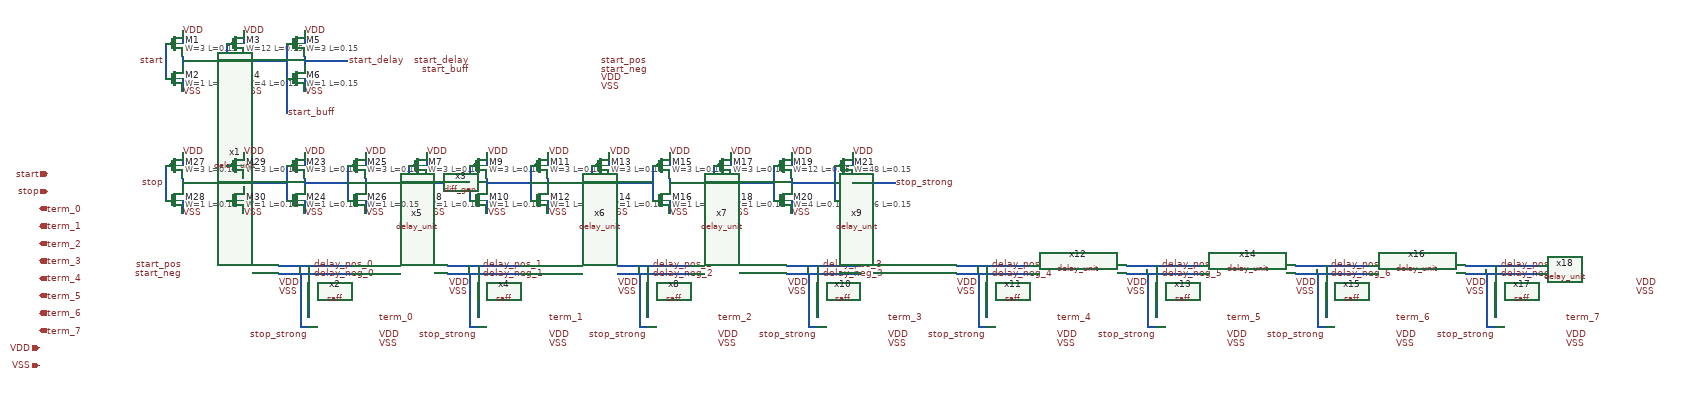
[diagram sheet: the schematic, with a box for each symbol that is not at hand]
v {xschem version=3.4.5 file_version=1.2
}
G {}
K {}
V {}
S {}
E {}
N 600 -270 770 -270 {
lab=delay_pos_0}
N 600 -250 770 -250 {
lab=delay_neg_0}
N 990 -270 1160 -270 {
lab=delay_pos_1}
N 990 -250 1160 -250 {
lab=delay_neg_1}
N 1380 -270 1550 -270 {
lab=delay_pos_2}
N 1380 -250 1550 -250 {
lab=delay_neg_2}
N 380 -750 380 -730 {
lab=#net1}
N 340 -780 340 -700 {
lab=start}
N 380 -810 380 -780 {
lab=VDD}
N 380 -700 380 -670 {
lab=VSS}
N 520 -750 520 -730 {
lab=start_buff}
N 480 -780 480 -700 {
lab=#net1}
N 520 -810 520 -780 {
lab=VDD}
N 520 -700 520 -670 {
lab=VSS}
N 660 -750 660 -730 {
lab=start_delay}
N 620 -780 620 -700 {
lab=start_buff}
N 660 -810 660 -780 {
lab=VDD}
N 660 -700 660 -670 {
lab=VSS}
N 380 -740 480 -740 {
lab=#net1}
N 520 -740 620 -740 {
lab=start_buff}
N 660 -740 760 -740 {
lab=start_delay}
N 620 -700 620 -620 {
lab=start_buff}
N 940 -470 940 -450 {
lab=#net2}
N 900 -500 900 -420 {
lab=#net3}
N 940 -530 940 -500 {
lab=VDD}
N 940 -420 940 -390 {
lab=VSS}
N 1080 -470 1080 -450 {
lab=#net4}
N 1040 -500 1040 -420 {
lab=#net2}
N 1080 -530 1080 -500 {
lab=VDD}
N 1080 -420 1080 -390 {
lab=VSS}
N 940 -460 1040 -460 {
lab=#net2}
N 1220 -470 1220 -450 {
lab=#net5}
N 1180 -500 1180 -420 {
lab=#net4}
N 1220 -530 1220 -500 {
lab=VDD}
N 1220 -420 1220 -390 {
lab=VSS}
N 1080 -460 1180 -460 {
lab=#net4}
N 1360 -470 1360 -450 {
lab=#net6}
N 1320 -500 1320 -420 {
lab=#net5}
N 1360 -530 1360 -500 {
lab=VDD}
N 1360 -420 1360 -390 {
lab=VSS}
N 1220 -460 1320 -460 {
lab=#net5}
N 1500 -470 1500 -450 {
lab=#net7}
N 1460 -500 1460 -420 {
lab=#net6}
N 1500 -530 1500 -500 {
lab=VDD}
N 1500 -420 1500 -390 {
lab=VSS}
N 1360 -460 1460 -460 {
lab=#net6}
N 1640 -470 1640 -450 {
lab=#net8}
N 1600 -500 1600 -420 {
lab=#net7}
N 1640 -530 1640 -500 {
lab=VDD}
N 1640 -420 1640 -390 {
lab=VSS}
N 1500 -460 1600 -460 {
lab=#net7}
N 1780 -470 1780 -450 {
lab=#net9}
N 1740 -500 1740 -420 {
lab=#net8}
N 1780 -530 1780 -500 {
lab=VDD}
N 1780 -420 1780 -390 {
lab=VSS}
N 1920 -470 1920 -450 {
lab=stop_strong}
N 1880 -500 1880 -420 {
lab=#net9}
N 1920 -530 1920 -500 {
lab=VDD}
N 1920 -420 1920 -390 {
lab=VSS}
N 1780 -460 1880 -460 {
lab=#net9}
N 1640 -460 1740 -460 {
lab=#net8}
N 1920 -460 2020 -460 {
lab=stop_strong}
N 670 -270 670 -150 {
lab=delay_pos_0}
N 650 -250 650 -130 {
lab=delay_neg_0}
N 650 -130 670 -130 {
lab=delay_neg_0}
N 1060 -270 1060 -150 {
lab=delay_pos_1}
N 1040 -250 1040 -130 {
lab=delay_neg_1}
N 1040 -130 1060 -130 {
lab=delay_neg_1}
N 1450 -270 1450 -150 {
lab=delay_pos_2}
N 1430 -250 1430 -130 {
lab=delay_neg_2}
N 1430 -130 1450 -130 {
lab=delay_neg_2}
N 1820 -250 1820 -130 {
lab=delay_neg_3}
N 1820 -130 1840 -130 {
lab=delay_neg_3}
N 2230 -270 2230 -150 {
lab=delay_pos_4}
N 2210 -250 2210 -130 {
lab=delay_neg_4}
N 2210 -130 2230 -130 {
lab=delay_neg_4}
N 1770 -250 1940 -250 {
lab=delay_neg_3}
N 1770 -270 1940 -270 {
lab=delay_pos_3}
N 1840 -270 1840 -150 {
lab=delay_pos_3}
N 2160 -250 2330 -250 {
lab=delay_neg_4}
N 2160 -270 2330 -270 {
lab=delay_pos_4}
N 660 -470 660 -450 {
lab=#net10}
N 620 -500 620 -420 {
lab=#net11}
N 660 -530 660 -500 {
lab=VDD}
N 660 -420 660 -390 {
lab=VSS}
N 800 -470 800 -450 {
lab=#net3}
N 760 -500 760 -420 {
lab=#net10}
N 800 -530 800 -500 {
lab=VDD}
N 800 -420 800 -390 {
lab=VSS}
N 660 -460 760 -460 {
lab=#net10}
N 800 -460 900 -460 {
lab=#net3}
N 380 -470 380 -450 {
lab=#net12}
N 340 -500 340 -420 {
lab=stop}
N 380 -530 380 -500 {
lab=VDD}
N 380 -420 380 -390 {
lab=VSS}
N 520 -470 520 -450 {
lab=#net11}
N 480 -500 480 -420 {
lab=#net12}
N 520 -530 520 -500 {
lab=VDD}
N 520 -420 520 -390 {
lab=VSS}
N 380 -460 480 -460 {
lab=#net12}
N 520 -460 620 -460 {
lab=#net11}
N 2620 -270 2620 -150 {
lab=delay_pos_4}
N 2600 -250 2600 -130 {
lab=delay_neg_4}
N 2600 -130 2620 -130 {
lab=delay_neg_4}
N 2550 -250 2720 -250 {
lab=delay_neg_4}
N 2550 -270 2720 -270 {
lab=delay_pos_4}
N 3010 -270 3010 -150 {
lab=delay_pos_4}
N 2990 -250 2990 -130 {
lab=delay_neg_4}
N 2990 -130 3010 -130 {
lab=delay_neg_4}
N 2940 -250 3110 -250 {
lab=delay_neg_4}
N 2940 -270 3110 -270 {
lab=delay_pos_4}
N 3400 -270 3400 -150 {
lab=delay_pos_4}
N 3380 -250 3380 -130 {
lab=delay_neg_4}
N 3380 -130 3400 -130 {
lab=delay_neg_4}
N 3330 -250 3500 -250 {
lab=delay_neg_4}
N 3330 -270 3500 -270 {
lab=delay_pos_4}
C {devices/iopin.sym} 50 -80 0 0 {name=p1 lab=VDD}
C {devices/iopin.sym} 50 -40 0 0 {name=p2 lab=VSS}
C {devices/ipin.sym} 70 -480 0 0 {name=p3 lab=start}
C {devices/ipin.sym} 70 -440 0 0 {name=p4 lab=stop}
C {diff_gen.sym} 1190 -710 0 0 {name=x3}
C {devices/lab_pin.sym} 1340 -680 2 0 {name=p15 sig_type=std_logic lab=VSS
}
C {devices/lab_pin.sym} 1340 -700 2 0 {name=p5 sig_type=std_logic lab=VDD
}
C {devices/lab_pin.sym} 830 -90 2 0 {name=p6 sig_type=std_logic lab=VSS
}
C {devices/lab_pin.sym} 830 -110 2 0 {name=p7 sig_type=std_logic lab=VDD
}
C {devices/lab_pin.sym} 600 -230 2 0 {name=p8 sig_type=std_logic lab=VDD
}
C {devices/lab_pin.sym} 600 -210 2 0 {name=p9 sig_type=std_logic lab=VSS
}
C {devices/lab_pin.sym} 1220 -90 2 0 {name=p10 sig_type=std_logic lab=VSS
}
C {devices/lab_pin.sym} 1220 -110 2 0 {name=p11 sig_type=std_logic lab=VDD
}
C {devices/lab_pin.sym} 990 -230 2 0 {name=p12 sig_type=std_logic lab=VDD
}
C {devices/lab_pin.sym} 990 -210 2 0 {name=p13 sig_type=std_logic lab=VSS
}
C {devices/lab_pin.sym} 830 -150 2 0 {name=p14 sig_type=std_logic lab=term_0
}
C {devices/lab_pin.sym} 1220 -150 2 0 {name=p16 sig_type=std_logic lab=term_1
}
C {devices/lab_pin.sym} 1610 -90 2 0 {name=p17 sig_type=std_logic lab=VSS
}
C {devices/lab_pin.sym} 1610 -110 2 0 {name=p18 sig_type=std_logic lab=VDD
}
C {devices/lab_pin.sym} 1380 -230 2 0 {name=p19 sig_type=std_logic lab=VDD
}
C {devices/lab_pin.sym} 1380 -210 2 0 {name=p20 sig_type=std_logic lab=VSS
}
C {devices/lab_pin.sym} 1610 -150 2 0 {name=p21 sig_type=std_logic lab=term_2
}
C {devices/lab_pin.sym} 1770 -230 2 0 {name=p24 sig_type=std_logic lab=VDD
}
C {devices/lab_pin.sym} 1770 -210 2 0 {name=p25 sig_type=std_logic lab=VSS
}
C {devices/lab_pin.sym} 670 -110 2 1 {name=p32 sig_type=std_logic lab=stop_strong
}
C {devices/lab_pin.sym} 1060 -110 0 0 {name=p33 sig_type=std_logic lab=stop_strong
}
C {sky130_fd_pr/pfet_01v8.sym} 360 -780 0 0 {name=M1
L=0.15
W=3
nf=1
mult=1
ad="'int((nf+1)/2) * W/nf * 0.29'" 
pd="'2*int((nf+1)/2) * (W/nf + 0.29)'"
as="'int((nf+2)/2) * W/nf * 0.29'" 
ps="'2*int((nf+2)/2) * (W/nf + 0.29)'"
nrd="'0.29 / W'" nrs="'0.29 / W'"
sa=0 sb=0 sd=0
model=pfet_01v8
spiceprefix=X
}
C {sky130_fd_pr/nfet_01v8.sym} 360 -700 0 0 {name=M2
L=0.15
W=1
nf=1 
mult=1
ad="'int((nf+1)/2) * W/nf * 0.29'" 
pd="'2*int((nf+1)/2) * (W/nf + 0.29)'"
as="'int((nf+2)/2) * W/nf * 0.29'" 
ps="'2*int((nf+2)/2) * (W/nf + 0.29)'"
nrd="'0.29 / W'" nrs="'0.29 / W'"
sa=0 sb=0 sd=0
model=nfet_01v8
spiceprefix=X
}
C {devices/lab_pin.sym} 380 -670 0 1 {name=p37 sig_type=std_logic lab=VSS}
C {devices/lab_pin.sym} 380 -810 0 1 {name=p38 sig_type=std_logic lab=VDD}
C {sky130_fd_pr/pfet_01v8.sym} 500 -780 0 0 {name=M3
L=0.15
W=12
nf=1
mult=1
ad="'int((nf+1)/2) * W/nf * 0.29'" 
pd="'2*int((nf+1)/2) * (W/nf + 0.29)'"
as="'int((nf+2)/2) * W/nf * 0.29'" 
ps="'2*int((nf+2)/2) * (W/nf + 0.29)'"
nrd="'0.29 / W'" nrs="'0.29 / W'"
sa=0 sb=0 sd=0
model=pfet_01v8
spiceprefix=X
}
C {sky130_fd_pr/nfet_01v8.sym} 500 -700 0 0 {name=M4
L=0.15
W=4
nf=1 
mult=1
ad="'int((nf+1)/2) * W/nf * 0.29'" 
pd="'2*int((nf+1)/2) * (W/nf + 0.29)'"
as="'int((nf+2)/2) * W/nf * 0.29'" 
ps="'2*int((nf+2)/2) * (W/nf + 0.29)'"
nrd="'0.29 / W'" nrs="'0.29 / W'"
sa=0 sb=0 sd=0
model=nfet_01v8
spiceprefix=X
}
C {devices/lab_pin.sym} 520 -670 0 1 {name=p39 sig_type=std_logic lab=VSS}
C {devices/lab_pin.sym} 520 -810 0 1 {name=p40 sig_type=std_logic lab=VDD}
C {sky130_fd_pr/pfet_01v8.sym} 640 -780 0 0 {name=M5
L=0.15
W=3
nf=1
mult=1
ad="'int((nf+1)/2) * W/nf * 0.29'" 
pd="'2*int((nf+1)/2) * (W/nf + 0.29)'"
as="'int((nf+2)/2) * W/nf * 0.29'" 
ps="'2*int((nf+2)/2) * (W/nf + 0.29)'"
nrd="'0.29 / W'" nrs="'0.29 / W'"
sa=0 sb=0 sd=0
model=pfet_01v8
spiceprefix=X
}
C {sky130_fd_pr/nfet_01v8.sym} 640 -700 0 0 {name=M6
L=0.15
W=1
nf=1 
mult=1
ad="'int((nf+1)/2) * W/nf * 0.29'" 
pd="'2*int((nf+1)/2) * (W/nf + 0.29)'"
as="'int((nf+2)/2) * W/nf * 0.29'" 
ps="'2*int((nf+2)/2) * (W/nf + 0.29)'"
nrd="'0.29 / W'" nrs="'0.29 / W'"
sa=0 sb=0 sd=0
model=nfet_01v8
spiceprefix=X
}
C {devices/lab_pin.sym} 660 -670 0 1 {name=p41 sig_type=std_logic lab=VSS}
C {devices/lab_pin.sym} 660 -810 0 1 {name=p42 sig_type=std_logic lab=VDD}
C {devices/lab_wire.sym} 760 -740 0 1 {name=p43 sig_type=std_logic lab=start_delay}
C {devices/lab_wire.sym} 620 -620 0 1 {name=p44 sig_type=std_logic lab=start_buff}
C {devices/lab_pin.sym} 1040 -740 0 0 {name=p45 sig_type=std_logic lab=start_delay}
C {devices/lab_pin.sym} 1040 -720 0 0 {name=p46 sig_type=std_logic lab=start_buff}
C {devices/lab_wire.sym} 340 -740 0 0 {name=p47 sig_type=std_logic lab=start}
C {sky130_fd_pr/pfet_01v8.sym} 920 -500 0 0 {name=M7
L=0.15
W=3
nf=1
mult=1
ad="'int((nf+1)/2) * W/nf * 0.29'" 
pd="'2*int((nf+1)/2) * (W/nf + 0.29)'"
as="'int((nf+2)/2) * W/nf * 0.29'" 
ps="'2*int((nf+2)/2) * (W/nf + 0.29)'"
nrd="'0.29 / W'" nrs="'0.29 / W'"
sa=0 sb=0 sd=0
model=pfet_01v8
spiceprefix=X
}
C {sky130_fd_pr/nfet_01v8.sym} 920 -420 0 0 {name=M8
L=0.15
W=1
nf=1 
mult=1
ad="'int((nf+1)/2) * W/nf * 0.29'" 
pd="'2*int((nf+1)/2) * (W/nf + 0.29)'"
as="'int((nf+2)/2) * W/nf * 0.29'" 
ps="'2*int((nf+2)/2) * (W/nf + 0.29)'"
nrd="'0.29 / W'" nrs="'0.29 / W'"
sa=0 sb=0 sd=0
model=nfet_01v8
spiceprefix=X
}
C {devices/lab_pin.sym} 940 -390 0 1 {name=p50 sig_type=std_logic lab=VSS}
C {devices/lab_pin.sym} 940 -530 0 1 {name=p51 sig_type=std_logic lab=VDD}
C {devices/lab_wire.sym} 340 -460 0 0 {name=p52 sig_type=std_logic lab=stop}
C {sky130_fd_pr/pfet_01v8.sym} 1060 -500 0 0 {name=M9
L=0.15
W=3
nf=1
mult=1
ad="'int((nf+1)/2) * W/nf * 0.29'" 
pd="'2*int((nf+1)/2) * (W/nf + 0.29)'"
as="'int((nf+2)/2) * W/nf * 0.29'" 
ps="'2*int((nf+2)/2) * (W/nf + 0.29)'"
nrd="'0.29 / W'" nrs="'0.29 / W'"
sa=0 sb=0 sd=0
model=pfet_01v8
spiceprefix=X
}
C {sky130_fd_pr/nfet_01v8.sym} 1060 -420 0 0 {name=M10
L=0.15
W=1
nf=1 
mult=1
ad="'int((nf+1)/2) * W/nf * 0.29'" 
pd="'2*int((nf+1)/2) * (W/nf + 0.29)'"
as="'int((nf+2)/2) * W/nf * 0.29'" 
ps="'2*int((nf+2)/2) * (W/nf + 0.29)'"
nrd="'0.29 / W'" nrs="'0.29 / W'"
sa=0 sb=0 sd=0
model=nfet_01v8
spiceprefix=X
}
C {devices/lab_pin.sym} 1080 -390 0 1 {name=p53 sig_type=std_logic lab=VSS}
C {devices/lab_pin.sym} 1080 -530 0 1 {name=p54 sig_type=std_logic lab=VDD}
C {sky130_fd_pr/pfet_01v8.sym} 1200 -500 0 0 {name=M11
L=0.15
W=3
nf=1
mult=1
ad="'int((nf+1)/2) * W/nf * 0.29'" 
pd="'2*int((nf+1)/2) * (W/nf + 0.29)'"
as="'int((nf+2)/2) * W/nf * 0.29'" 
ps="'2*int((nf+2)/2) * (W/nf + 0.29)'"
nrd="'0.29 / W'" nrs="'0.29 / W'"
sa=0 sb=0 sd=0
model=pfet_01v8
spiceprefix=X
}
C {sky130_fd_pr/nfet_01v8.sym} 1200 -420 0 0 {name=M12
L=0.15
W=1
nf=1 
mult=1
ad="'int((nf+1)/2) * W/nf * 0.29'" 
pd="'2*int((nf+1)/2) * (W/nf + 0.29)'"
as="'int((nf+2)/2) * W/nf * 0.29'" 
ps="'2*int((nf+2)/2) * (W/nf + 0.29)'"
nrd="'0.29 / W'" nrs="'0.29 / W'"
sa=0 sb=0 sd=0
model=nfet_01v8
spiceprefix=X
}
C {devices/lab_pin.sym} 1220 -390 0 1 {name=p55 sig_type=std_logic lab=VSS}
C {devices/lab_pin.sym} 1220 -530 0 1 {name=p56 sig_type=std_logic lab=VDD}
C {sky130_fd_pr/pfet_01v8.sym} 1340 -500 0 0 {name=M13
L=0.15
W=3
nf=1
mult=1
ad="'int((nf+1)/2) * W/nf * 0.29'" 
pd="'2*int((nf+1)/2) * (W/nf + 0.29)'"
as="'int((nf+2)/2) * W/nf * 0.29'" 
ps="'2*int((nf+2)/2) * (W/nf + 0.29)'"
nrd="'0.29 / W'" nrs="'0.29 / W'"
sa=0 sb=0 sd=0
model=pfet_01v8
spiceprefix=X
}
C {sky130_fd_pr/nfet_01v8.sym} 1340 -420 0 0 {name=M14
L=0.15
W=1
nf=1 
mult=1
ad="'int((nf+1)/2) * W/nf * 0.29'" 
pd="'2*int((nf+1)/2) * (W/nf + 0.29)'"
as="'int((nf+2)/2) * W/nf * 0.29'" 
ps="'2*int((nf+2)/2) * (W/nf + 0.29)'"
nrd="'0.29 / W'" nrs="'0.29 / W'"
sa=0 sb=0 sd=0
model=nfet_01v8
spiceprefix=X
}
C {devices/lab_pin.sym} 1360 -390 0 1 {name=p57 sig_type=std_logic lab=VSS}
C {devices/lab_pin.sym} 1360 -530 0 1 {name=p58 sig_type=std_logic lab=VDD}
C {sky130_fd_pr/pfet_01v8.sym} 1480 -500 0 0 {name=M15
L=0.15
W=3
nf=1
mult=1
ad="'int((nf+1)/2) * W/nf * 0.29'" 
pd="'2*int((nf+1)/2) * (W/nf + 0.29)'"
as="'int((nf+2)/2) * W/nf * 0.29'" 
ps="'2*int((nf+2)/2) * (W/nf + 0.29)'"
nrd="'0.29 / W'" nrs="'0.29 / W'"
sa=0 sb=0 sd=0
model=pfet_01v8
spiceprefix=X
}
C {sky130_fd_pr/nfet_01v8.sym} 1480 -420 0 0 {name=M16
L=0.15
W=1
nf=1 
mult=1
ad="'int((nf+1)/2) * W/nf * 0.29'" 
pd="'2*int((nf+1)/2) * (W/nf + 0.29)'"
as="'int((nf+2)/2) * W/nf * 0.29'" 
ps="'2*int((nf+2)/2) * (W/nf + 0.29)'"
nrd="'0.29 / W'" nrs="'0.29 / W'"
sa=0 sb=0 sd=0
model=nfet_01v8
spiceprefix=X
}
C {devices/lab_pin.sym} 1500 -390 0 1 {name=p59 sig_type=std_logic lab=VSS}
C {devices/lab_pin.sym} 1500 -530 0 1 {name=p60 sig_type=std_logic lab=VDD}
C {sky130_fd_pr/pfet_01v8.sym} 1620 -500 0 0 {name=M17
L=0.15
W=3
nf=1
mult=1
ad="'int((nf+1)/2) * W/nf * 0.29'" 
pd="'2*int((nf+1)/2) * (W/nf + 0.29)'"
as="'int((nf+2)/2) * W/nf * 0.29'" 
ps="'2*int((nf+2)/2) * (W/nf + 0.29)'"
nrd="'0.29 / W'" nrs="'0.29 / W'"
sa=0 sb=0 sd=0
model=pfet_01v8
spiceprefix=X
}
C {sky130_fd_pr/nfet_01v8.sym} 1620 -420 0 0 {name=M18
L=0.15
W=1
nf=1 
mult=1
ad="'int((nf+1)/2) * W/nf * 0.29'" 
pd="'2*int((nf+1)/2) * (W/nf + 0.29)'"
as="'int((nf+2)/2) * W/nf * 0.29'" 
ps="'2*int((nf+2)/2) * (W/nf + 0.29)'"
nrd="'0.29 / W'" nrs="'0.29 / W'"
sa=0 sb=0 sd=0
model=nfet_01v8
spiceprefix=X
}
C {devices/lab_pin.sym} 1640 -390 0 1 {name=p61 sig_type=std_logic lab=VSS}
C {devices/lab_pin.sym} 1640 -530 0 1 {name=p62 sig_type=std_logic lab=VDD}
C {sky130_fd_pr/pfet_01v8.sym} 1760 -500 0 0 {name=M19
L=0.15
W=12
nf=1
mult=1
ad="'int((nf+1)/2) * W/nf * 0.29'" 
pd="'2*int((nf+1)/2) * (W/nf + 0.29)'"
as="'int((nf+2)/2) * W/nf * 0.29'" 
ps="'2*int((nf+2)/2) * (W/nf + 0.29)'"
nrd="'0.29 / W'" nrs="'0.29 / W'"
sa=0 sb=0 sd=0
model=pfet_01v8
spiceprefix=X
}
C {sky130_fd_pr/nfet_01v8.sym} 1760 -420 0 0 {name=M20
L=0.15
W=4
nf=1 
mult=1
ad="'int((nf+1)/2) * W/nf * 0.29'" 
pd="'2*int((nf+1)/2) * (W/nf + 0.29)'"
as="'int((nf+2)/2) * W/nf * 0.29'" 
ps="'2*int((nf+2)/2) * (W/nf + 0.29)'"
nrd="'0.29 / W'" nrs="'0.29 / W'"
sa=0 sb=0 sd=0
model=nfet_01v8
spiceprefix=X
}
C {devices/lab_pin.sym} 1780 -390 0 1 {name=p63 sig_type=std_logic lab=VSS}
C {devices/lab_pin.sym} 1780 -530 0 1 {name=p64 sig_type=std_logic lab=VDD}
C {sky130_fd_pr/pfet_01v8.sym} 1900 -500 0 0 {name=M21
L=0.15
W=48
nf=1
mult=1
ad="'int((nf+1)/2) * W/nf * 0.29'" 
pd="'2*int((nf+1)/2) * (W/nf + 0.29)'"
as="'int((nf+2)/2) * W/nf * 0.29'" 
ps="'2*int((nf+2)/2) * (W/nf + 0.29)'"
nrd="'0.29 / W'" nrs="'0.29 / W'"
sa=0 sb=0 sd=0
model=pfet_01v8
spiceprefix=X
}
C {sky130_fd_pr/nfet_01v8.sym} 1900 -420 0 0 {name=M22
L=0.15
W=16
nf=1 
mult=1
ad="'int((nf+1)/2) * W/nf * 0.29'" 
pd="'2*int((nf+1)/2) * (W/nf + 0.29)'"
as="'int((nf+2)/2) * W/nf * 0.29'" 
ps="'2*int((nf+2)/2) * (W/nf + 0.29)'"
nrd="'0.29 / W'" nrs="'0.29 / W'"
sa=0 sb=0 sd=0
model=nfet_01v8
spiceprefix=X
}
C {devices/lab_pin.sym} 1920 -390 0 1 {name=p65 sig_type=std_logic lab=VSS}
C {devices/lab_pin.sym} 1920 -530 0 1 {name=p66 sig_type=std_logic lab=VDD}
C {devices/lab_wire.sym} 2020 -460 0 1 {name=p67 sig_type=std_logic lab=stop_strong}
C {devices/opin.sym} 50 -400 0 0 {name=p68 lab=term_0}
C {devices/opin.sym} 50 -360 0 0 {name=p69 lab=term_1}
C {devices/opin.sym} 50 -320 0 0 {name=p70 lab=term_2}
C {devices/opin.sym} 50 -280 0 0 {name=p71 lab=term_3}
C {devices/opin.sym} 50 -240 0 0 {name=p72 lab=term_4}
C {devices/lab_wire.sym} 680 -270 0 1 {name=p73 sig_type=std_logic lab=delay_pos_0}
C {devices/lab_wire.sym} 680 -250 0 1 {name=p74 sig_type=std_logic lab=delay_neg_0}
C {devices/lab_wire.sym} 1070 -270 0 1 {name=p75 sig_type=std_logic lab=delay_pos_1}
C {devices/lab_wire.sym} 1070 -250 0 1 {name=p76 sig_type=std_logic lab=delay_neg_1}
C {delay_unit.sym} 490 -240 0 0 {name=x1}
C {saff.sym} 750 -120 0 0 {name=x2}
C {saff.sym} 1140 -120 0 0 {name=x4}
C {delay_unit.sym} 880 -240 0 0 {name=x5}
C {delay_unit.sym} 1270 -240 0 0 {name=x6}
C {devices/lab_wire.sym} 1460 -270 0 1 {name=p77 sig_type=std_logic lab=delay_pos_2}
C {devices/lab_wire.sym} 1460 -250 0 1 {name=p78 sig_type=std_logic lab=delay_neg_2}
C {delay_unit.sym} 1660 -240 0 0 {name=x7}
C {saff.sym} 1530 -120 0 0 {name=x8}
C {devices/lab_pin.sym} 1450 -110 0 0 {name=p79 sig_type=std_logic lab=stop_strong
}
C {devices/lab_wire.sym} 1850 -270 0 1 {name=p80 sig_type=std_logic lab=delay_pos_3}
C {devices/lab_wire.sym} 1850 -250 0 1 {name=p81 sig_type=std_logic lab=delay_neg_3}
C {devices/lab_pin.sym} 2160 -230 2 0 {name=p82 sig_type=std_logic lab=VDD
}
C {devices/lab_pin.sym} 2160 -210 2 0 {name=p83 sig_type=std_logic lab=VSS
}
C {delay_unit.sym} 2050 -240 0 0 {name=x9}
C {devices/lab_wire.sym} 2240 -270 0 1 {name=p84 sig_type=std_logic lab=delay_pos_4}
C {devices/lab_wire.sym} 2240 -250 0 1 {name=p85 sig_type=std_logic lab=delay_neg_4}
C {devices/lab_pin.sym} 2000 -90 2 0 {name=p86 sig_type=std_logic lab=VSS
}
C {devices/lab_pin.sym} 2000 -110 2 0 {name=p87 sig_type=std_logic lab=VDD
}
C {devices/lab_pin.sym} 2000 -150 2 0 {name=p88 sig_type=std_logic lab=term_3
}
C {saff.sym} 1920 -120 0 0 {name=x10}
C {devices/lab_pin.sym} 1840 -110 0 0 {name=p89 sig_type=std_logic lab=stop_strong
}
C {devices/lab_pin.sym} 2390 -90 2 0 {name=p22 sig_type=std_logic lab=VSS
}
C {devices/lab_pin.sym} 2390 -110 2 0 {name=p23 sig_type=std_logic lab=VDD
}
C {devices/lab_pin.sym} 2390 -150 2 0 {name=p26 sig_type=std_logic lab=term_4
}
C {saff.sym} 2310 -120 0 0 {name=x11}
C {devices/lab_pin.sym} 2230 -110 0 0 {name=p29 sig_type=std_logic lab=stop_strong
}
C {delay_unit.sym} 2440 -240 0 0 {name=x12}
C {devices/lab_pin.sym} 1340 -720 0 1 {name=p27 sig_type=std_logic lab=start_neg}
C {devices/lab_pin.sym} 1340 -740 0 1 {name=p28 sig_type=std_logic lab=start_pos}
C {devices/lab_pin.sym} 380 -250 0 0 {name=p30 sig_type=std_logic lab=start_neg}
C {devices/lab_pin.sym} 380 -270 0 0 {name=p31 sig_type=std_logic lab=start_pos}
C {devices/lab_pin.sym} 2550 -230 2 0 {name=p34 sig_type=std_logic lab=VDD
}
C {devices/lab_pin.sym} 2550 -210 2 0 {name=p35 sig_type=std_logic lab=VSS
}
C {sky130_fd_pr/pfet_01v8.sym} 640 -500 0 0 {name=M23
L=0.15
W=3
nf=1
mult=1
ad="'int((nf+1)/2) * W/nf * 0.29'" 
pd="'2*int((nf+1)/2) * (W/nf + 0.29)'"
as="'int((nf+2)/2) * W/nf * 0.29'" 
ps="'2*int((nf+2)/2) * (W/nf + 0.29)'"
nrd="'0.29 / W'" nrs="'0.29 / W'"
sa=0 sb=0 sd=0
model=pfet_01v8
spiceprefix=X
}
C {sky130_fd_pr/nfet_01v8.sym} 640 -420 0 0 {name=M24
L=0.15
W=1
nf=1 
mult=1
ad="'int((nf+1)/2) * W/nf * 0.29'" 
pd="'2*int((nf+1)/2) * (W/nf + 0.29)'"
as="'int((nf+2)/2) * W/nf * 0.29'" 
ps="'2*int((nf+2)/2) * (W/nf + 0.29)'"
nrd="'0.29 / W'" nrs="'0.29 / W'"
sa=0 sb=0 sd=0
model=nfet_01v8
spiceprefix=X
}
C {devices/lab_pin.sym} 660 -390 0 1 {name=p36 sig_type=std_logic lab=VSS}
C {devices/lab_pin.sym} 660 -530 0 1 {name=p48 sig_type=std_logic lab=VDD}
C {sky130_fd_pr/pfet_01v8.sym} 780 -500 0 0 {name=M25
L=0.15
W=3
nf=1
mult=1
ad="'int((nf+1)/2) * W/nf * 0.29'" 
pd="'2*int((nf+1)/2) * (W/nf + 0.29)'"
as="'int((nf+2)/2) * W/nf * 0.29'" 
ps="'2*int((nf+2)/2) * (W/nf + 0.29)'"
nrd="'0.29 / W'" nrs="'0.29 / W'"
sa=0 sb=0 sd=0
model=pfet_01v8
spiceprefix=X
}
C {sky130_fd_pr/nfet_01v8.sym} 780 -420 0 0 {name=M26
L=0.15
W=1
nf=1 
mult=1
ad="'int((nf+1)/2) * W/nf * 0.29'" 
pd="'2*int((nf+1)/2) * (W/nf + 0.29)'"
as="'int((nf+2)/2) * W/nf * 0.29'" 
ps="'2*int((nf+2)/2) * (W/nf + 0.29)'"
nrd="'0.29 / W'" nrs="'0.29 / W'"
sa=0 sb=0 sd=0
model=nfet_01v8
spiceprefix=X
}
C {devices/lab_pin.sym} 800 -390 0 1 {name=p49 sig_type=std_logic lab=VSS}
C {devices/lab_pin.sym} 800 -530 0 1 {name=p90 sig_type=std_logic lab=VDD}
C {sky130_fd_pr/pfet_01v8.sym} 360 -500 0 0 {name=M27
L=0.15
W=3
nf=1
mult=1
ad="'int((nf+1)/2) * W/nf * 0.29'" 
pd="'2*int((nf+1)/2) * (W/nf + 0.29)'"
as="'int((nf+2)/2) * W/nf * 0.29'" 
ps="'2*int((nf+2)/2) * (W/nf + 0.29)'"
nrd="'0.29 / W'" nrs="'0.29 / W'"
sa=0 sb=0 sd=0
model=pfet_01v8
spiceprefix=X
}
C {sky130_fd_pr/nfet_01v8.sym} 360 -420 0 0 {name=M28
L=0.15
W=1
nf=1 
mult=1
ad="'int((nf+1)/2) * W/nf * 0.29'" 
pd="'2*int((nf+1)/2) * (W/nf + 0.29)'"
as="'int((nf+2)/2) * W/nf * 0.29'" 
ps="'2*int((nf+2)/2) * (W/nf + 0.29)'"
nrd="'0.29 / W'" nrs="'0.29 / W'"
sa=0 sb=0 sd=0
model=nfet_01v8
spiceprefix=X
}
C {devices/lab_pin.sym} 380 -390 0 1 {name=p91 sig_type=std_logic lab=VSS}
C {devices/lab_pin.sym} 380 -530 0 1 {name=p92 sig_type=std_logic lab=VDD}
C {sky130_fd_pr/pfet_01v8.sym} 500 -500 0 0 {name=M29
L=0.15
W=3
nf=1
mult=1
ad="'int((nf+1)/2) * W/nf * 0.29'" 
pd="'2*int((nf+1)/2) * (W/nf + 0.29)'"
as="'int((nf+2)/2) * W/nf * 0.29'" 
ps="'2*int((nf+2)/2) * (W/nf + 0.29)'"
nrd="'0.29 / W'" nrs="'0.29 / W'"
sa=0 sb=0 sd=0
model=pfet_01v8
spiceprefix=X
}
C {sky130_fd_pr/nfet_01v8.sym} 500 -420 0 0 {name=M30
L=0.15
W=1
nf=1 
mult=1
ad="'int((nf+1)/2) * W/nf * 0.29'" 
pd="'2*int((nf+1)/2) * (W/nf + 0.29)'"
as="'int((nf+2)/2) * W/nf * 0.29'" 
ps="'2*int((nf+2)/2) * (W/nf + 0.29)'"
nrd="'0.29 / W'" nrs="'0.29 / W'"
sa=0 sb=0 sd=0
model=nfet_01v8
spiceprefix=X
}
C {devices/lab_pin.sym} 520 -390 0 1 {name=p93 sig_type=std_logic lab=VSS}
C {devices/lab_pin.sym} 520 -530 0 1 {name=p94 sig_type=std_logic lab=VDD}
C {devices/lab_wire.sym} 2630 -270 0 1 {name=p95 sig_type=std_logic lab=delay_pos_5}
C {devices/lab_wire.sym} 2630 -250 0 1 {name=p96 sig_type=std_logic lab=delay_neg_5}
C {devices/lab_pin.sym} 2780 -90 2 0 {name=p97 sig_type=std_logic lab=VSS
}
C {devices/lab_pin.sym} 2780 -110 2 0 {name=p98 sig_type=std_logic lab=VDD
}
C {devices/lab_pin.sym} 2780 -150 2 0 {name=p99 sig_type=std_logic lab=term_5
}
C {saff.sym} 2700 -120 0 0 {name=x13}
C {devices/lab_pin.sym} 2620 -110 0 0 {name=p100 sig_type=std_logic lab=stop_strong
}
C {delay_unit.sym} 2830 -240 0 0 {name=x14}
C {devices/lab_pin.sym} 2940 -230 2 0 {name=p101 sig_type=std_logic lab=VDD
}
C {devices/lab_pin.sym} 2940 -210 2 0 {name=p102 sig_type=std_logic lab=VSS
}
C {devices/lab_wire.sym} 3020 -270 0 1 {name=p103 sig_type=std_logic lab=delay_pos_6}
C {devices/lab_wire.sym} 3020 -250 0 1 {name=p104 sig_type=std_logic lab=delay_neg_6}
C {devices/lab_pin.sym} 3170 -90 2 0 {name=p105 sig_type=std_logic lab=VSS
}
C {devices/lab_pin.sym} 3170 -110 2 0 {name=p106 sig_type=std_logic lab=VDD
}
C {devices/lab_pin.sym} 3170 -150 2 0 {name=p107 sig_type=std_logic lab=term_6
}
C {saff.sym} 3090 -120 0 0 {name=x15}
C {devices/lab_pin.sym} 3010 -110 0 0 {name=p108 sig_type=std_logic lab=stop_strong
}
C {delay_unit.sym} 3220 -240 0 0 {name=x16}
C {devices/lab_pin.sym} 3330 -230 2 0 {name=p109 sig_type=std_logic lab=VDD
}
C {devices/lab_pin.sym} 3330 -210 2 0 {name=p110 sig_type=std_logic lab=VSS
}
C {devices/lab_wire.sym} 3410 -270 0 1 {name=p111 sig_type=std_logic lab=delay_pos_7}
C {devices/lab_wire.sym} 3410 -250 0 1 {name=p112 sig_type=std_logic lab=delay_neg_7}
C {devices/lab_pin.sym} 3560 -90 2 0 {name=p113 sig_type=std_logic lab=VSS
}
C {devices/lab_pin.sym} 3560 -110 2 0 {name=p114 sig_type=std_logic lab=VDD
}
C {devices/lab_pin.sym} 3560 -150 2 0 {name=p115 sig_type=std_logic lab=term_7
}
C {saff.sym} 3480 -120 0 0 {name=x17}
C {devices/lab_pin.sym} 3400 -110 0 0 {name=p116 sig_type=std_logic lab=stop_strong
}
C {delay_unit.sym} 3610 -240 0 0 {name=x18}
C {devices/lab_pin.sym} 3720 -230 2 0 {name=p117 sig_type=std_logic lab=VDD
}
C {devices/lab_pin.sym} 3720 -210 2 0 {name=p118 sig_type=std_logic lab=VSS
}
C {devices/opin.sym} 50 -200 0 0 {name=p119 lab=term_5}
C {devices/opin.sym} 50 -160 0 0 {name=p120 lab=term_6}
C {devices/opin.sym} 50 -120 0 0 {name=p121 lab=term_7}
